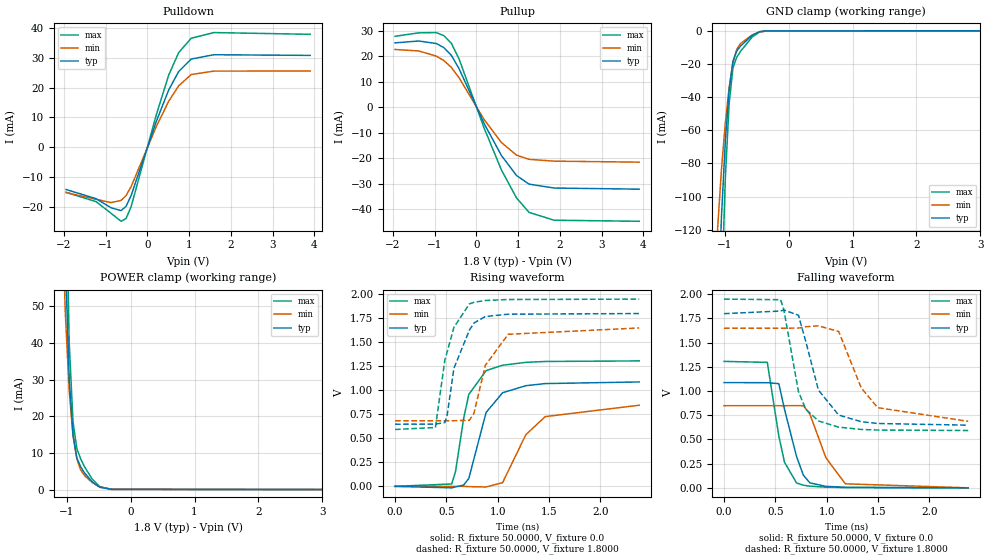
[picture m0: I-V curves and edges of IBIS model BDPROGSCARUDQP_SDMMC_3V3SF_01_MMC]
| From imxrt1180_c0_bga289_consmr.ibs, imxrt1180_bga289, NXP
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[Model]  BDPROGSCARUDQP_SDMMC_3V3SF_01_MMC
|   Model BDPROGSCARUDQP_SDMMC_3V3SF_01_MMC
| This model was characterised for following simulation conditions:
| External (pad) voltage:
|   - Typ: 1.8V,   - Min: 1.65V,   - Max: 1.95V
| Library cells for typ/min/max conditions are connected as defined below:
|  IO - External Pad
|  A - Core Input
|  EN - Output Buffer Enable
|  ASRCN3V3[0] - gnde REFH3V3 gnde
|  ASRCN3V3[1] - REFH3V3 gnde gnde
|  ASRCN3V3[2] - gnde
|  ASRCN3V3[3] - gnde REFH3V3 gnde
|  ASRCP3V3[0] - vdde3v3 vdde3v3 REFL3V3
|  ASRCP3V3[1] - vdde3v3 REFL3V3 vdde3v3
|  ASRCP3V3[2] - REFL3V3 vdde3v3 vdde3v3
|  ASRCP3V3[3] - vdde3v3 REFL3V3 vdde3v3
|  IOGC - NC
|  PDRV - vdd
|  PSW - gnd
|  REFH3V3 - REFH3V3
|  REFL3V3 - REFL3V3
|  ZI - NC
|  gnd - gnd
|  gnde - gnde
|  vdd - vdd
|  vdde3v3 - vdde3v3
| All other pins connected to ground
Model_type I/O
Polarity   Non-Inverting
Enable   Active-Low
Vinl =   0.5775V
Vinh =   1.2675V
Vmeas =  0.9000V
Cref =   30.0000pF
Rref =   1.0000M
Vref =   1.8000V
C_comp   2.2202pF   2.2061pF   2.2431pF
|C_comp_pullup   1.1648pF   1.1334pF   1.1989pF
|C_comp_pulldown   0.7687pF   0.7946pF   0.7484pF
[Model Spec]
| variable   typ   min   max
Vinh   1.1700V   1.0725V   1.2675V
Vinl   0.6300V   0.5775V   0.6825V
[Temperature Range]   25.0000   0.1050k   -20.0000
[Voltage Range]   1.8000V   1.6500V   1.9500V
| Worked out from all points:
|   slope of the pulldown table from 0 to 0.27 V, typ, clamps not added: 24.9 ohm
|   slope of the pullup table from 0 to 0.27 V, typ, clamps not added: 29.4 ohm
|   GND clamp passes 1 mA (typ) near -0.49 V on its own axis
|   POWER clamp passes 1 mA (typ) near -0.52 V on its own axis
|   rising waveform, R_fixture 50.0000, V_fixture 0.0: 20-80 % time 187ps typ, 278ps min, 143ps max; typ from 0 V to 1.09 V
|   rising waveform, R_fixture 50.0000, V_fixture 1.8000: 20-80 % time 176ps typ, 209ps min, 151ps max; typ from 0.647 V to 1.8 V
|   falling waveform, R_fixture 50.0000, V_fixture 0.0: 20-80 % time 160ps typ, 207ps min, 131ps max; typ from 1.09 V to 0 V
|   falling waveform, R_fixture 50.0000, V_fixture 1.8000: 20-80 % time 199ps typ, 260ps min, 163ps max; typ from 1.8 V to 0.648 V
[Pulldown]
|Voltage   I(typ)   I(min)   I(max)
-1.95V    -14.21mA   -15.24mA   -15.16mA
-1.23V    -17.29mA   -17.49mA   -18.29mA
-870mV    -20.35mA   -18.61mA   -22.21mA
-630mV    -21.29mA   -17.87mA   -24.88mA
-510mV    -19.83mA   -16.21mA   -23.94mA
-390mV    -16.22mA   -13.24mA   -19.93mA
210mV     8.519mA    6.826mA    10.73mA
510mV     19.18mA    15.4mA     24.16mA
750mV     25.39mA    20.6mA     31.74mA
1.05V     29.56mA    24.36mA    36.54mA
1.59V     31mA       25.51mA    38.44mA
3.9V      30.78mA    25.54mA    37.85mA
[Pullup]
|Voltage   I(typ)   I(min)   I(max)
-1.95V    25.33mA    22.73mA    27.91mA
-1.38V    26.06mA    22.15mA    29.26mA
-960mV    25.07mA    20.12mA    29.37mA
-780mV    23.45mA    18.36mA    28.17mA
-600mV    20.41mA    15.67mA    25.13mA
-420mV    15.32mA    11.72mA    19.18mA
180mV     -6.218mA   -4.683mA   -7.944mA
600mV     -18.93mA   -13.83mA   -24.61mA
960mV     -26.73mA   -18.74mA   -35.55mA
1.26V     -30.13mA   -20.39mA   -41.21mA
1.86V     -31.66mA   -21.11mA   -44.29mA
3.9V      -32.11mA   -21.5mA    -44.72mA
[GND_clamp]
|Voltage   I(typ)   I(min)   I(max)
-1.95V    -1.789A    -1.03A     -2.95A
-1.11V    -176.3mA   -119.2mA   -277.9mA
-1.05V    -112.3mA   -83.66mA   -163.2mA
-990mV    -66.82mA   -55.78mA   -89.16mA
-930mV    -35.58mA   -34.18mA   -43.87mA
-870mV    -18.33mA   -19.06mA   -22.3mA
-810mV    -12.12mA   -11.08mA   -15.87mA
-750mV    -9.12mA    -7.575mA   -12.28mA
-570mV    -2.717mA   -2.477mA   -3.751mA
-450mV    -466.5uA   -625uA     -610.9uA
-330mV    -31.46uA   -57.07uA   -36.76uA
3.9V      0A         0A         0A
[POWER_clamp]
|Voltage   I(typ)   I(min)   I(max)
-1.95V    1.733A     983.2mA    2.899A
-1.08V    123mA      81.32mA    204.7mA
-1.02V    63.28mA    48.12mA    95.46mA
-960mV    30.45mA    27.05mA    40.34mA
-900mV    14.89mA    14.83mA    18.42mA
-840mV    8.668mA    8.37mA     11.21mA
-780mV    6.192mA    5.372mA    8.379mA
-720mV    4.573mA    3.84mA     6.25mA
-600mV    2.107mA    1.918mA    2.859mA
-480mV    625.6uA    714.7uA    800.1uA
-300mV    67.29uA    79.42uA    85.49uA
3.9V      0A         0A         0A
[Ramp]
| variable   typ   min   max
dV/dt_r  0.6518/0.1871n   0.5067/0.2778n   0.7834/0.1433n
dV/dt_f  0.6910/0.1987n   0.5773/0.2598n   0.8140/0.1626n
R_load = 50.0000
[Rising Waveform]
R_fixture= 50.0000
V_fixture= 0.0
V_fixture_min= 0.0
V_fixture_max= 0.0
|time   V(typ)   V(min)   V(max)
0s        166.1uV    140.5uV    208.2uV
551.8ps   -15.45mV   125uV      25.17mV
588.8ps   -5.716mV   208uV      150.4mV
669.4ps   13.92mV    477.8uV    711.8mV
719ps     82.64mV    -2.741mV   957.1mV
887.5ps   769.3mV    -6.272mV   1.205V
1.048ns   974.4mV    38.32mV    1.261V
1.275ns   1.048V     538.1mV    1.291V
1.464ns   1.07V      726.2mV    1.3V
2.38ns    1.087V     844.6mV    1.306V
[Rising Waveform]
R_fixture= 50.0000
V_fixture= 1.8000
V_fixture_min= 1.6500
V_fixture_max= 1.9500
|time   V(typ)   V(min)   V(max)
0s        647.2mV    682.9mV    592.2mV
393.6ps   647.6mV    683mV      612.8mV
485.6ps   665mV      683.1mV    1.317V
508.9ps   745.6mV    683.1mV    1.403V
573.7ps   1.229V     683.4mV    1.655V
724.3ps   1.625V     688.1mV    1.899V
768.7ps   1.7V       759.1mV    1.916V
880.3ps   1.768V     1.261V     1.935V
1.103ns   1.792V     1.583V     1.945V
2.38ns    1.799V     1.649V     1.949V
[Falling Waveform]
R_fixture= 50.0000
V_fixture= 0.0
V_fixture_min= 0.0
V_fixture_max= 0.0
|time   V(typ)   V(min)   V(max)
0s        1.087V     848.5mV    1.306V
421.4ps   1.086V     848.6mV    1.296V
533.7ps   1.076V     848.6mV    535.5mV
589.3ps   810.4mV    848.4mV    264.3mV
706.5ps   324mV      849.4mV    50.66mV
773.3ps   130.1mV    848.1mV    27.28mV
836.9ps   51.51mV    760.3mV    17.68mV
992ps     15.88mV    312.7mV    7.454mV
1.182ns   6.105mV    42.07mV    3.027mV
2.38ns    194.4uV    401.9uV    215.4uV
[Falling Waveform]
R_fixture= 50.0000
V_fixture= 1.8000
V_fixture_min= 1.6500
V_fixture_max= 1.9500
|time   V(typ)   V(min)   V(max)
0s        1.799V     1.649V     1.949V
550.9ps   1.826V     1.649V     1.943V
581ps     1.837V     1.649V     1.848V
724.9ps   1.783V     1.65V      994.8mV
796.4ps   1.512V     1.664V     812.7mV
919.6ps   1.01V      1.673V     691.4mV
1.117ns   751.8mV    1.615V     627.1mV
1.337ns   683.4mV    1.032V     603.4mV
1.497ns   664.7mV    828.2mV    597.2mV
2.38ns    647.5mV    687.1mV    592.3mV
